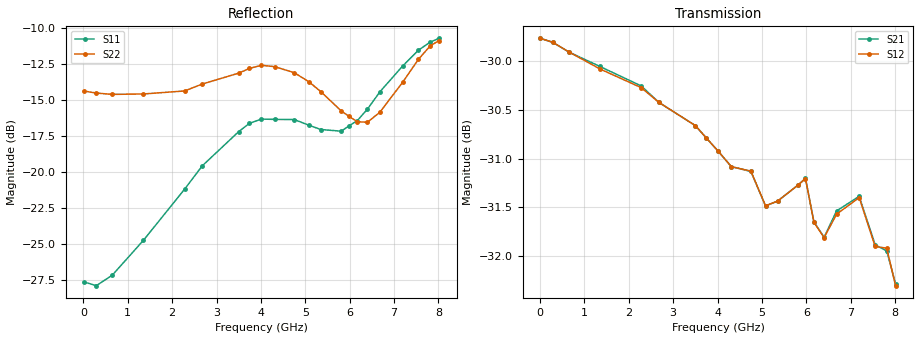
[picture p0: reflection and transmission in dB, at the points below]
! DEVICE ID: PE43712
! File Path: z:\PE43713\PE43713_CHAR_NOM_04292014\AMB\3p300\LS_ATT_28p50dB\PE43713_AMB_3p300V_3p000V_0p000V_LS_ATT_28p50dB_S2P_SN_10_A0139A.s2p
! Serial: 10
! Lot: A0139A
! Temp: 25C
! VDD: 3.300
! VSS: 0.000
! Control_Hi: 3.000
! Control_Lo: 0.000
! Attenuation Step: 28.50dB
! Port 1: RF1
! Port 2: RF2
! ThroughPath:1-2
! IDD: 0.0001454936
! ISS: -9.71e-008
#  Hz  S  RI  R  50
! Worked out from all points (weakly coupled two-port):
!   801 points, 10 MHz to 8.01 GHz, reference 50 ohm
!   highest |S21| = -29.76 dB at 10 MHz (marker M1); lowest = -32.3 dB at 8.01 GHz (marker M2)
!   lowest |S11| = -27.9 dB at 290 MHz (marker M3), VSWR 1.08, Z = 46.3 + j1.23 ohm
!   |S11| at or under -10 dB: start of sweep to end of sweep
!   |S22| runs from -16.5 to -10.9 dB; largest |S21 - S12| = 0.00013
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1e7  -0.0416 0.000894  0.0325 -0.000129  0.0325 -0.000133  -0.1915 0.00123
2.9e8  -0.0381 0.0133  0.0322 -0.00306  0.0322 -0.00306  -0.1873 0.0207
6.5e8  -0.0337 0.0281  0.0313 -0.00655  0.0313 -0.00657  -0.181 0.0446
1.35e9  -0.021 0.054  0.0288 -0.0126  0.0287 -0.0126  -0.1648 0.0885
2.28e9  0.0095 0.0868  0.0239 -0.0193  0.0239 -0.0192  -0.1258 0.1445
2.68e9  0.025 0.1023  0.0211 -0.0215  0.0211 -0.0215  -0.1047 0.1734
3.5e9  0.0484 0.1297  0.0153 -0.025  0.0153 -0.025  -0.073 0.2086
3.74e9  0.0533 0.1379  0.0134 -0.0256  0.0134 -0.0256  -0.0681 0.2191
4.01e9  0.0582 0.1415  0.0113 -0.0261  0.0113 -0.0261  -0.064 0.2264
4.31e9  0.0617 0.1396  0.00909 -0.0264  0.00909 -0.0264  -0.0548 0.2262
4.75e9  0.072 0.1344  0.00602 -0.0271  0.00607 -0.0271  -0.0409 0.218
5.08e9  0.0815 0.1207  0.00365 -0.0264  0.0037 -0.0264  -0.0297 0.2041
5.35e9  0.0911 0.1073  0.00234 -0.0267  0.00234 -0.0267  -0.0189 0.1896
5.81e9  0.1136 0.0799  -0.000939 -0.0273  -0.000871 -0.0273  0.0181 0.1623
5.98e9  0.1262 0.0709  -0.00273 -0.0274  -0.00268 -0.0274  0.0356 0.1525
6.17e9  0.1385 0.0602  -0.00429 -0.0258  -0.00421 -0.0258  0.0571 0.1385
6.4e9  0.1573 0.0521  -0.00441 -0.0253  -0.00434 -0.0253  0.0854 0.1223
6.68e9  0.1852 0.0435  -0.00602 -0.0258  -0.006 -0.0257  0.1213 0.1068
7.19e9  0.2308 0.036  -0.0108 -0.0247  -0.0107 -0.0247  0.1802 0.098
7.55e9  0.2629 0.0373  -0.0128 -0.022  -0.0127 -0.022  0.2252 0.1013
7.81e9  0.28 0.0407  -0.0139 -0.0211  -0.0139 -0.0212  0.253 0.1062
8.01e9  0.2886 0.0433  -0.0141 -0.0198  -0.014 -0.0198  0.2663 0.106
